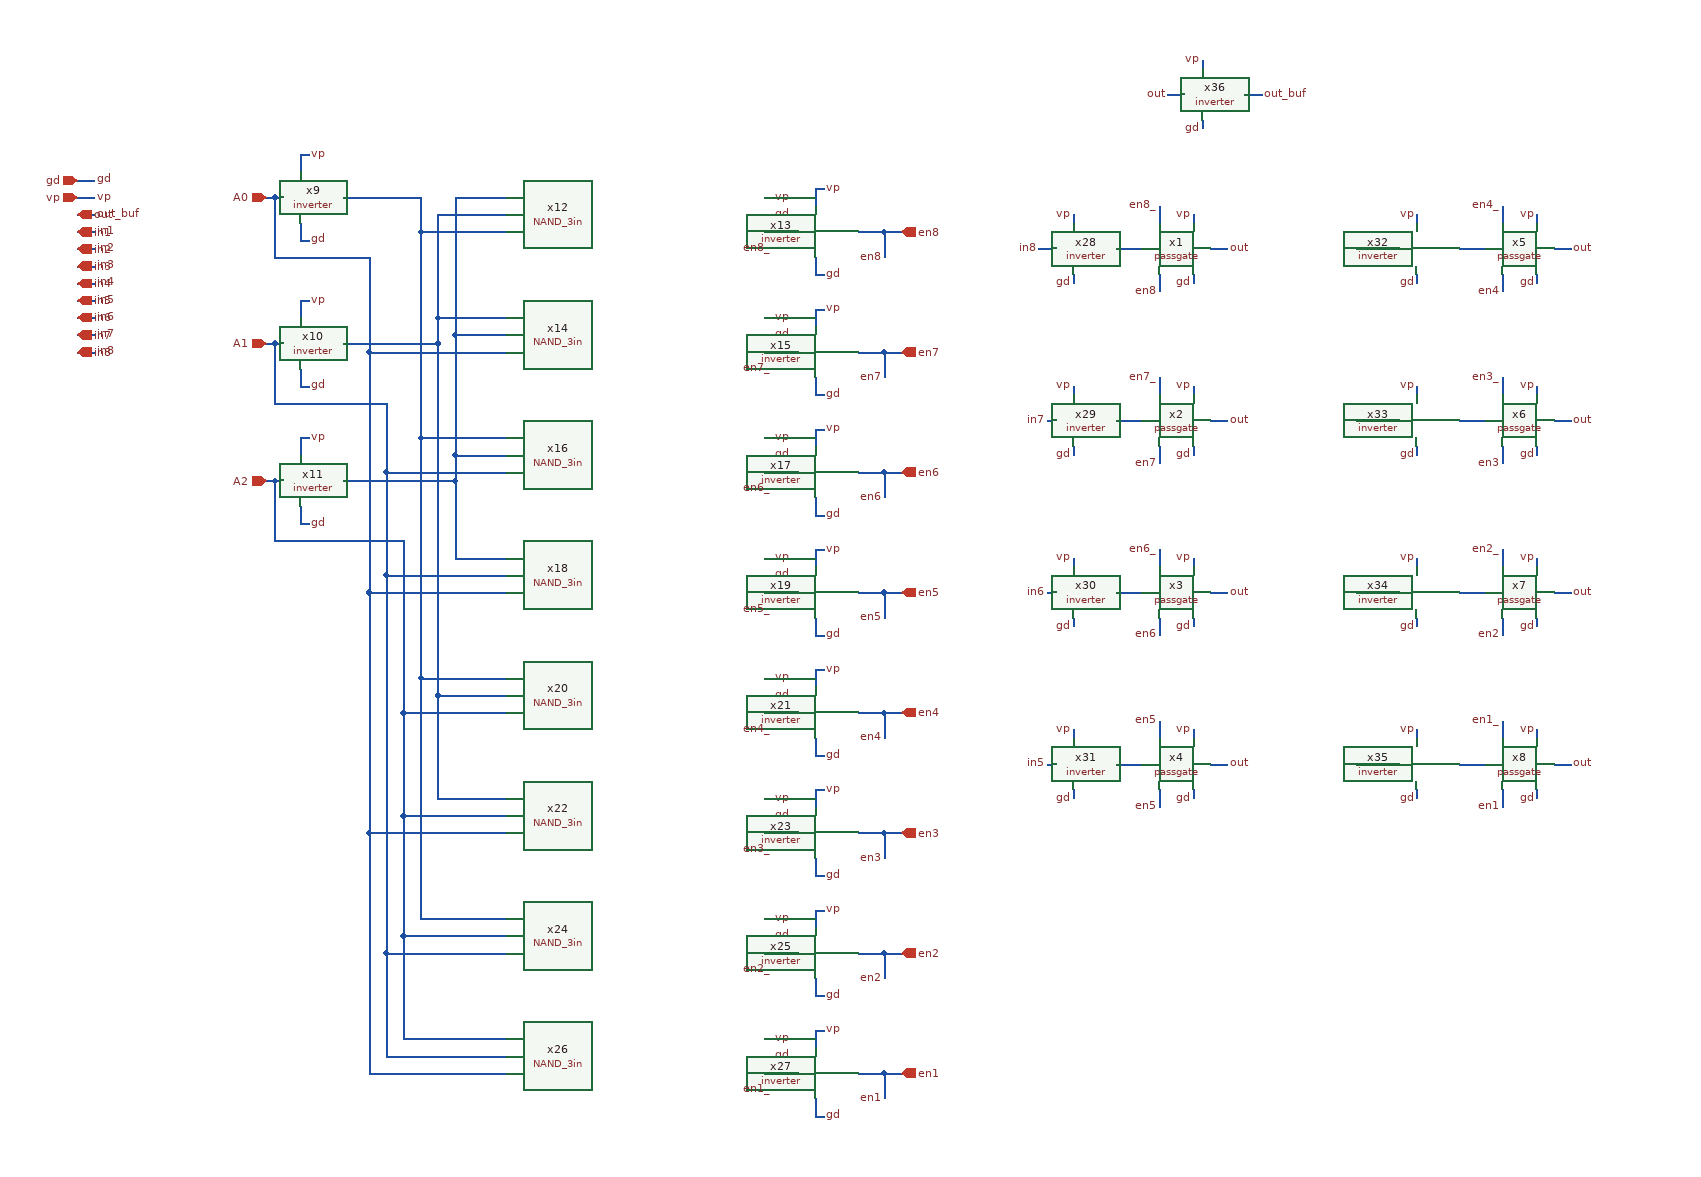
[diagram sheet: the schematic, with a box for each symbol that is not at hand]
v {xschem version=3.4.8RC file_version=1.3}
G {}
K {}
V {}
S {}
F {}
E {}
N 80 -100 100 -100 {lab=gd}
N 80 -80 100 -80 {lab=vp}
N 80 -60 100 -60 {lab=out}
N 80 -40 100 -40 {lab=in1}
N 80 -20 100 -20 {lab=in2}
N 80 0 100 0 {lab=in3}
N 80 20 100 20 {lab=in4}
N 80 60 100 60 {lab=in6}
N 80 80 100 80 {lab=in7}
N 80 100 100 100 {lab=in8}
N 1340 -70 1340 -50 {lab=en8_}
N 1340 10 1340 30 {lab=en8}
N 1380 10 1380 20 {lab=gd}
N 1380 -60 1380 -50 {lab=vp}
N 1400 -20 1420 -20 {lab=out}
N 1340 130 1340 150 {lab=en7_}
N 1340 210 1340 230 {lab=en7}
N 1380 210 1380 220 {lab=gd}
N 1380 140 1380 150 {lab=vp}
N 1210 180 1220 180 {lab=in7}
N 1400 180 1420 180 {lab=out}
N 80 40 100 40 {lab=in5}
N 1340 330 1340 350 {lab=en6_}
N 1340 410 1340 430 {lab=en6}
N 1380 410 1380 420 {lab=gd}
N 1380 340 1380 350 {lab=vp}
N 1210 380 1220 380 {lab=in6}
N 1400 380 1420 380 {lab=out}
N 1340 530 1340 550 {lab=en5}
N 1340 610 1340 630 {lab=en5}
N 1380 610 1380 620 {lab=gd}
N 1380 540 1380 550 {lab=vp}
N 1210 580 1220 580 {lab=in5}
N 1400 580 1420 580 {lab=out}
N 1740 -70 1740 -50 {lab=en4_}
N 1740 10 1740 30 {lab=en4}
N 1780 10 1780 20 {lab=gd}
N 1780 -60 1780 -50 {lab=vp}
N 1570 -20 1580 -20 {lab=#net1}
N 1800 -20 1820 -20 {lab=out}
N 1740 130 1740 150 {lab=en3_}
N 1740 210 1740 230 {lab=en3}
N 1780 210 1780 220 {lab=gd}
N 1780 140 1780 150 {lab=vp}
N 1570 180 1580 180 {lab=#net2}
N 1800 180 1820 180 {lab=out}
N 1740 330 1740 350 {lab=en2_}
N 1740 410 1740 430 {lab=en2}
N 1780 410 1780 420 {lab=gd}
N 1780 340 1780 350 {lab=vp}
N 1570 380 1580 380 {lab=#net3}
N 1800 380 1820 380 {lab=out}
N 1740 530 1740 550 {lab=en1_}
N 1740 610 1740 630 {lab=en1}
N 1780 610 1780 620 {lab=gd}
N 1780 540 1780 550 {lab=vp}
N 1570 580 1580 580 {lab=#net4}
N 1800 580 1820 580 {lab=out}
N 340 -130 350 -130 {lab=vp}
N 340 -130 340 -110 {lab=vp}
N 340 -30 350 -30 {lab=gd}
N 340 -50 340 -30 {lab=gd}
N 310 -80 320 -80 {lab=A0}
N 340 40 350 40 {lab=vp}
N 340 40 340 60 {lab=vp}
N 340 140 350 140 {lab=gd}
N 340 120 340 140 {lab=gd}
N 310 90 320 90 {lab=A1}
N 340 200 350 200 {lab=vp}
N 340 200 340 220 {lab=vp}
N 340 300 350 300 {lab=gd}
N 340 280 340 300 {lab=gd}
N 310 250 320 250 {lab=A2}
N 880 -80 890 -80 {lab=vp}
N 880 -60 890 -60 {lab=gd}
N 940 -90 950 -90 {lab=vp}
N 940 -90 940 -70 {lab=vp}
N 940 10 950 10 {lab=gd}
N 940 -10 940 10 {lab=gd}
N 890 -40 920 -40 {lab=en8_}
N 990 -40 1020 -40 {lab=en8}
N 890 -40 890 -20 {lab=en8_}
N 880 -40 890 -40 {lab=en8_}
N 1020 -40 1020 -10 {lab=en8}
N 880 60 890 60 {lab=vp}
N 880 80 890 80 {lab=gd}
N 940 50 950 50 {lab=vp}
N 940 50 940 70 {lab=vp}
N 940 150 950 150 {lab=gd}
N 940 130 940 150 {lab=gd}
N 890 100 920 100 {lab=en7_}
N 990 100 1020 100 {lab=en7}
N 890 100 890 120 {lab=en7_}
N 880 100 890 100 {lab=en7_}
N 1020 100 1020 130 {lab=en7}
N 880 200 890 200 {lab=vp}
N 880 220 890 220 {lab=gd}
N 940 190 950 190 {lab=vp}
N 940 190 940 210 {lab=vp}
N 940 290 950 290 {lab=gd}
N 940 270 940 290 {lab=gd}
N 890 240 920 240 {lab=en6_}
N 990 240 1020 240 {lab=en6}
N 890 240 890 260 {lab=en6_}
N 880 240 890 240 {lab=en6_}
N 1020 240 1020 270 {lab=en6}
N 880 340 890 340 {lab=vp}
N 880 360 890 360 {lab=gd}
N 940 330 950 330 {lab=vp}
N 940 330 940 350 {lab=vp}
N 940 430 950 430 {lab=gd}
N 940 410 940 430 {lab=gd}
N 890 380 920 380 {lab=en5_}
N 990 380 1020 380 {lab=en5}
N 890 380 890 400 {lab=en5_}
N 880 380 890 380 {lab=en5_}
N 1020 380 1020 410 {lab=en5}
N 880 480 890 480 {lab=vp}
N 880 500 890 500 {lab=gd}
N 940 470 950 470 {lab=vp}
N 940 470 940 490 {lab=vp}
N 940 570 950 570 {lab=gd}
N 940 550 940 570 {lab=gd}
N 890 520 920 520 {lab=en4_}
N 990 520 1020 520 {lab=en4}
N 890 520 890 540 {lab=en4_}
N 880 520 890 520 {lab=en4_}
N 1020 520 1020 550 {lab=en4}
N 880 620 890 620 {lab=vp}
N 880 640 890 640 {lab=gd}
N 940 610 950 610 {lab=vp}
N 940 610 940 630 {lab=vp}
N 940 710 950 710 {lab=gd}
N 940 690 940 710 {lab=gd}
N 890 660 920 660 {lab=en3_}
N 990 660 1020 660 {lab=en3}
N 890 660 890 680 {lab=en3_}
N 880 660 890 660 {lab=en3_}
N 1020 660 1020 690 {lab=en3}
N 880 760 890 760 {lab=vp}
N 880 780 890 780 {lab=gd}
N 940 750 950 750 {lab=vp}
N 940 750 940 770 {lab=vp}
N 940 850 950 850 {lab=gd}
N 940 830 940 850 {lab=gd}
N 890 800 920 800 {lab=en2_}
N 990 800 1020 800 {lab=en2}
N 890 800 890 820 {lab=en2_}
N 880 800 890 800 {lab=en2_}
N 1020 800 1020 830 {lab=en2}
N 880 900 890 900 {lab=vp}
N 880 920 890 920 {lab=gd}
N 940 890 950 890 {lab=vp}
N 940 890 940 910 {lab=vp}
N 940 990 950 990 {lab=gd}
N 940 970 940 990 {lab=gd}
N 890 940 920 940 {lab=en1_}
N 990 940 1020 940 {lab=en1}
N 890 940 890 960 {lab=en1_}
N 880 940 890 940 {lab=en1_}
N 1020 940 1020 970 {lab=en1}
N 420 660 420 940 {lab=A0}
N 310 -80 310 -10 {lab=A0}
N 300 -80 310 -80 {lab=A0}
N 310 -10 420 -10 {lab=A0}
N 310 90 310 160 {lab=A1}
N 300 90 310 90 {lab=A1}
N 310 160 440 160 {lab=A1}
N 310 250 310 320 {lab=A2}
N 300 250 310 250 {lab=A2}
N 310 320 460 320 {lab=A2}
N 390 -80 480 -80 {lab=#net5}
N 390 90 500 90 {lab=#net6}
N 500 60 500 90 {lab=#net6}
N 390 250 520 250 {lab=#net7}
N 520 220 520 250 {lab=#net7}
N 480 -40 580 -40 {lab=#net5}
N 480 -80 480 -40 {lab=#net5}
N 500 -60 580 -60 {lab=#net6}
N 520 -80 580 -80 {lab=#net7}
N 480 200 580 200 {lab=#net5}
N 480 -40 480 200 {lab=#net5}
N 480 480 580 480 {lab=#net5}
N 480 200 480 480 {lab=#net5}
N 480 760 580 760 {lab=#net5}
N 480 480 480 760 {lab=#net5}
N 500 60 580 60 {lab=#net6}
N 500 -60 500 60 {lab=#net6}
N 500 620 580 620 {lab=#net6}
N 500 500 500 620 {lab=#net6}
N 500 500 580 500 {lab=#net6}
N 500 90 500 500 {lab=#net6}
N 520 80 580 80 {lab=#net7}
N 520 -80 520 80 {lab=#net7}
N 520 220 580 220 {lab=#net7}
N 520 80 520 220 {lab=#net7}
N 520 340 580 340 {lab=#net7}
N 520 250 520 340 {lab=#net7}
N 460 900 580 900 {lab=A2}
N 460 780 460 900 {lab=A2}
N 460 780 580 780 {lab=A2}
N 460 640 460 780 {lab=A2}
N 460 640 580 640 {lab=A2}
N 460 520 460 640 {lab=A2}
N 460 520 580 520 {lab=A2}
N 460 320 460 520 {lab=A2}
N 440 920 580 920 {lab=A1}
N 440 800 440 920 {lab=A1}
N 440 800 580 800 {lab=A1}
N 440 360 440 800 {lab=A1}
N 440 240 580 240 {lab=A1}
N 440 160 440 240 {lab=A1}
N 440 360 580 360 {lab=A1}
N 440 240 440 360 {lab=A1}
N 420 100 580 100 {lab=A0}
N 420 -10 420 100 {lab=A0}
N 420 380 580 380 {lab=A0}
N 420 100 420 380 {lab=A0}
N 420 660 580 660 {lab=A0}
N 420 380 420 660 {lab=A0}
N 420 940 580 940 {lab=A0}
N 1020 -40 1040 -40 {lab=en8}
N 1020 100 1040 100 {lab=en7}
N 1020 240 1040 240 {lab=en6}
N 1020 380 1040 380 {lab=en5}
N 1020 520 1040 520 {lab=en4}
N 1020 660 1040 660 {lab=en3}
N 1020 800 1040 800 {lab=en2}
N 1020 940 1040 940 {lab=en1}
N 1290 -20 1320 -20 {lab=#net8}
N 1240 -60 1240 -50 {lab=vp}
N 1240 10 1240 20 {lab=gd}
N 1200 -20 1220 -20 {lab=in8}
N 1290 180 1320 180 {lab=#net9}
N 1240 140 1240 150 {lab=vp}
N 1240 210 1240 220 {lab=gd}
N 1290 380 1320 380 {lab=#net10}
N 1240 340 1240 350 {lab=vp}
N 1240 410 1240 420 {lab=gd}
N 1290 580 1320 580 {lab=#net11}
N 1240 540 1240 550 {lab=vp}
N 1240 610 1240 620 {lab=gd}
N 1610 180 1620 180 {lab=#net12}
N 1610 380 1620 380 {lab=#net13}
N 1610 580 1620 580 {lab=#net14}
N 1690 -20 1720 -20 {lab=#net15}
N 1640 -60 1640 -50 {lab=vp}
N 1640 10 1640 20 {lab=gd}
N 1600 -20 1620 -20 {lab=in4}
N 1690 180 1720 180 {lab=#net16}
N 1640 140 1640 150 {lab=vp}
N 1640 210 1640 220 {lab=gd}
N 1690 380 1720 380 {lab=#net17}
N 1640 340 1640 350 {lab=vp}
N 1640 410 1640 420 {lab=gd}
N 1690 580 1720 580 {lab=#net18}
N 1640 540 1640 550 {lab=vp}
N 1640 610 1640 620 {lab=gd}
N 1390 -240 1390 -230 {lab=vp}
N 1390 -170 1390 -160 {lab=gd}
N 1440 -200 1460 -200 {lab=out_buf}
N 1350 -200 1370 -200 {lab=out}
C {/foss/designs/CHIP-PLL/divider/schematics/passgate.sym} 1340 0 0 0 {name=x1}
C {iopin.sym} 80 -100 2 0 {name=p1 lab=gd}
C {lab_pin.sym} 100 -100 2 0 {name=p4 sig_type=std_logic lab=gd}
C {iopin.sym} 80 -80 2 0 {name=p5 lab=vp}
C {lab_pin.sym} 100 -80 2 0 {name=p6 sig_type=std_logic lab=vp}
C {opin.sym} 80 -60 2 0 {name=p2 lab=out}
C {lab_pin.sym} 100 -60 2 0 {name=p3 sig_type=std_logic lab=out_buf}
C {ipin.sym} 80 -40 2 1 {name=p7 lab=in1}
C {lab_pin.sym} 100 -40 2 0 {name=p8 sig_type=std_logic lab=in1}
C {ipin.sym} 80 -20 2 1 {name=p9 lab=in2}
C {lab_pin.sym} 100 -20 2 0 {name=p10 sig_type=std_logic lab=in2}
C {ipin.sym} 80 0 2 1 {name=p11 lab=in3}
C {lab_pin.sym} 100 0 2 0 {name=p12 sig_type=std_logic lab=in3}
C {ipin.sym} 80 20 2 1 {name=p13 lab=in4}
C {lab_pin.sym} 100 20 2 0 {name=p14 sig_type=std_logic lab=in4}
C {ipin.sym} 80 40 2 1 {name=p15 lab=in5}
C {lab_pin.sym} 100 40 2 0 {name=p16 sig_type=std_logic lab=in5}
C {ipin.sym} 80 60 2 1 {name=p17 lab=in6}
C {lab_pin.sym} 100 60 2 0 {name=p18 sig_type=std_logic lab=in6}
C {ipin.sym} 80 80 2 1 {name=p19 lab=in7}
C {lab_pin.sym} 100 80 2 0 {name=p20 sig_type=std_logic lab=in7}
C {ipin.sym} 80 100 2 1 {name=p21 lab=in8}
C {lab_pin.sym} 100 100 2 0 {name=p22 sig_type=std_logic lab=in8}
C {lab_pin.sym} 1380 20 3 0 {name=p23 sig_type=std_logic lab=gd}
C {lab_pin.sym} 1340 -70 1 0 {name=p25 sig_type=std_logic lab=en8_}
C {lab_pin.sym} 1340 30 3 0 {name=p26 sig_type=std_logic lab=en8}
C {lab_pin.sym} 1200 -20 0 0 {name=p27 sig_type=std_logic lab=in8}
C {lab_pin.sym} 1420 -20 2 0 {name=p28 sig_type=std_logic lab=out}
C {/foss/designs/CHIP-PLL/divider/schematics/passgate.sym} 1340 200 0 0 {name=x2}
C {lab_pin.sym} 1380 220 3 0 {name=p29 sig_type=std_logic lab=gd}
C {lab_pin.sym} 1340 130 1 0 {name=p31 sig_type=std_logic lab=en7_}
C {lab_pin.sym} 1340 230 3 0 {name=p32 sig_type=std_logic lab=en7}
C {lab_pin.sym} 1210 180 0 0 {name=p33 sig_type=std_logic lab=in7}
C {lab_pin.sym} 1420 180 2 0 {name=p34 sig_type=std_logic lab=out}
C {/foss/designs/CHIP-PLL/divider/schematics/passgate.sym} 1340 400 0 0 {name=x3}
C {lab_pin.sym} 1380 420 3 0 {name=p35 sig_type=std_logic lab=gd}
C {lab_pin.sym} 1340 330 1 0 {name=p37 sig_type=std_logic lab=en6_}
C {lab_pin.sym} 1340 430 3 0 {name=p38 sig_type=std_logic lab=en6}
C {lab_pin.sym} 1210 380 0 0 {name=p39 sig_type=std_logic lab=in6
}
C {lab_pin.sym} 1420 380 2 0 {name=p40 sig_type=std_logic lab=out}
C {/foss/designs/CHIP-PLL/divider/schematics/passgate.sym} 1340 600 0 0 {name=x4}
C {lab_pin.sym} 1380 620 3 0 {name=p41 sig_type=std_logic lab=gd}
C {lab_pin.sym} 1340 530 1 0 {name=p43 sig_type=std_logic lab=en5
_}
C {lab_pin.sym} 1340 630 3 0 {name=p44 sig_type=std_logic lab=en5}
C {lab_pin.sym} 1210 580 0 0 {name=p45 sig_type=std_logic lab=in5}
C {lab_pin.sym} 1420 580 2 0 {name=p46 sig_type=std_logic lab=out}
C {/foss/designs/CHIP-PLL/divider/schematics/passgate.sym} 1740 0 0 0 {name=x5}
C {lab_pin.sym} 1780 20 3 0 {name=p47 sig_type=std_logic lab=gd}
C {lab_pin.sym} 1740 -70 1 0 {name=p49 sig_type=std_logic lab=en4_}
C {lab_pin.sym} 1740 30 3 0 {name=p50 sig_type=std_logic lab=en4}
C {lab_pin.sym} 1600 -20 0 0 {name=p51 sig_type=std_logic lab=in4}
C {lab_pin.sym} 1820 -20 2 0 {name=p52 sig_type=std_logic lab=out}
C {/foss/designs/CHIP-PLL/divider/schematics/passgate.sym} 1740 200 0 0 {name=x6}
C {lab_pin.sym} 1780 220 3 0 {name=p53 sig_type=std_logic lab=gd}
C {lab_pin.sym} 1740 130 1 0 {name=p55 sig_type=std_logic lab=en3_}
C {lab_pin.sym} 1740 230 3 0 {name=p56 sig_type=std_logic lab=en3}
C {lab_pin.sym} 1600 180 0 0 {name=p57 sig_type=std_logic lab=in3}
C {lab_pin.sym} 1820 180 2 0 {name=p58 sig_type=std_logic lab=out}
C {/foss/designs/CHIP-PLL/divider/schematics/passgate.sym} 1740 400 0 0 {name=x7}
C {lab_pin.sym} 1780 420 3 0 {name=p59 sig_type=std_logic lab=gd}
C {lab_pin.sym} 1740 330 1 0 {name=p61 sig_type=std_logic lab=en2_}
C {lab_pin.sym} 1740 430 3 0 {name=p62 sig_type=std_logic lab=en2}
C {lab_pin.sym} 1600 380 0 0 {name=p63 sig_type=std_logic lab=in2}
C {lab_pin.sym} 1820 380 2 0 {name=p64 sig_type=std_logic lab=out}
C {/foss/designs/CHIP-PLL/divider/schematics/passgate.sym} 1740 600 0 0 {name=x8}
C {lab_pin.sym} 1780 620 3 0 {name=p65 sig_type=std_logic lab=gd}
C {lab_pin.sym} 1740 530 1 0 {name=p67 sig_type=std_logic lab=en1_
_}
C {lab_pin.sym} 1740 630 3 0 {name=p68 sig_type=std_logic lab=en1}
C {lab_pin.sym} 1600 580 0 0 {name=p69 sig_type=std_logic lab=in1}
C {lab_pin.sym} 1820 580 2 0 {name=p70 sig_type=std_logic lab=out}
C {/foss/designs/CHIP-PLL/divider/schematics/inverter.sym} 340 -80 0 0 {name=x9}
C {lab_pin.sym} 350 -30 2 0 {name=p71 sig_type=std_logic lab=gd}
C {lab_pin.sym} 350 -130 2 0 {name=p72 sig_type=std_logic lab=vp}
C {ipin.sym} 300 -80 0 0 {name=p73 lab=A0}
C {/foss/designs/CHIP-PLL/divider/schematics/inverter.sym} 340 90 0 0 {name=x10}
C {lab_pin.sym} 350 140 2 0 {name=p74 sig_type=std_logic lab=gd}
C {lab_pin.sym} 350 40 2 0 {name=p75 sig_type=std_logic lab=vp}
C {ipin.sym} 300 90 0 0 {name=p76 lab=A1}
C {/foss/designs/CHIP-PLL/divider/schematics/inverter.sym} 340 250 0 0 {name=x11}
C {lab_pin.sym} 350 300 2 0 {name=p77 sig_type=std_logic lab=gd}
C {lab_pin.sym} 350 200 2 0 {name=p78 sig_type=std_logic lab=vp}
C {ipin.sym} 300 250 0 0 {name=p79 lab=A2}
C {lab_pin.sym} 1380 -60 1 0 {name=p24 sig_type=std_logic lab=vp}
C {lab_pin.sym} 1780 -60 1 0 {name=p30 sig_type=std_logic lab=vp}
C {lab_pin.sym} 1380 140 1 0 {name=p36 sig_type=std_logic lab=vp}
C {lab_pin.sym} 1780 140 1 0 {name=p42 sig_type=std_logic lab=vp}
C {lab_pin.sym} 1380 340 1 0 {name=p48 sig_type=std_logic lab=vp}
C {lab_pin.sym} 1780 340 1 0 {name=p54 sig_type=std_logic lab=vp}
C {lab_pin.sym} 1380 540 1 0 {name=p60 sig_type=std_logic lab=vp}
C {lab_pin.sym} 1780 540 1 0 {name=p66 sig_type=std_logic lab=vp}
C {/foss/designs/CHIP-PLL/divider/schematics/NAND_3in.sym} 730 -60 0 0 {name=x12}
C {lab_pin.sym} 890 -80 2 0 {name=p80 sig_type=std_logic lab=vp}
C {lab_pin.sym} 890 -60 2 0 {name=p81 sig_type=std_logic lab=gd}
C {/foss/designs/CHIP-PLL/divider/schematics/inverter.sym} 940 -40 0 0 {name=x13}
C {lab_pin.sym} 950 10 2 0 {name=p82 sig_type=std_logic lab=gd}
C {lab_pin.sym} 950 -90 2 0 {name=p83 sig_type=std_logic lab=vp}
C {lab_pin.sym} 890 -20 3 0 {name=p84 sig_type=std_logic lab=en8_}
C {lab_pin.sym} 1020 -10 3 0 {name=p85 sig_type=std_logic lab=en8}
C {/foss/designs/CHIP-PLL/divider/schematics/NAND_3in.sym} 730 80 0 0 {name=x14}
C {lab_pin.sym} 890 60 2 0 {name=p86 sig_type=std_logic lab=vp}
C {lab_pin.sym} 890 80 2 0 {name=p87 sig_type=std_logic lab=gd}
C {/foss/designs/CHIP-PLL/divider/schematics/inverter.sym} 940 100 0 0 {name=x15}
C {lab_pin.sym} 950 150 2 0 {name=p88 sig_type=std_logic lab=gd}
C {lab_pin.sym} 950 50 2 0 {name=p89 sig_type=std_logic lab=vp}
C {lab_pin.sym} 890 120 3 0 {name=p90 sig_type=std_logic lab=en7_}
C {lab_pin.sym} 1020 130 3 0 {name=p91 sig_type=std_logic lab=en7}
C {/foss/designs/CHIP-PLL/divider/schematics/NAND_3in.sym} 730 220 0 0 {name=x16}
C {lab_pin.sym} 890 200 2 0 {name=p92 sig_type=std_logic lab=vp}
C {lab_pin.sym} 890 220 2 0 {name=p93 sig_type=std_logic lab=gd}
C {/foss/designs/CHIP-PLL/divider/schematics/inverter.sym} 940 240 0 0 {name=x17}
C {lab_pin.sym} 950 290 2 0 {name=p94 sig_type=std_logic lab=gd}
C {lab_pin.sym} 950 190 2 0 {name=p95 sig_type=std_logic lab=vp}
C {lab_pin.sym} 890 260 3 0 {name=p96 sig_type=std_logic lab=en6_}
C {lab_pin.sym} 1020 270 3 0 {name=p97 sig_type=std_logic lab=en6}
C {/foss/designs/CHIP-PLL/divider/schematics/NAND_3in.sym} 730 360 0 0 {name=x18}
C {lab_pin.sym} 890 340 2 0 {name=p98 sig_type=std_logic lab=vp}
C {lab_pin.sym} 890 360 2 0 {name=p99 sig_type=std_logic lab=gd}
C {/foss/designs/CHIP-PLL/divider/schematics/inverter.sym} 940 380 0 0 {name=x19}
C {lab_pin.sym} 950 430 2 0 {name=p100 sig_type=std_logic lab=gd}
C {lab_pin.sym} 950 330 2 0 {name=p101 sig_type=std_logic lab=vp}
C {lab_pin.sym} 890 400 3 0 {name=p102 sig_type=std_logic lab=en5_}
C {lab_pin.sym} 1020 410 3 0 {name=p103 sig_type=std_logic lab=en5}
C {/foss/designs/CHIP-PLL/divider/schematics/NAND_3in.sym} 730 500 0 0 {name=x20}
C {lab_pin.sym} 890 480 2 0 {name=p104 sig_type=std_logic lab=vp}
C {lab_pin.sym} 890 500 2 0 {name=p105 sig_type=std_logic lab=gd}
C {/foss/designs/CHIP-PLL/divider/schematics/inverter.sym} 940 520 0 0 {name=x21}
C {lab_pin.sym} 950 570 2 0 {name=p106 sig_type=std_logic lab=gd}
C {lab_pin.sym} 950 470 2 0 {name=p107 sig_type=std_logic lab=vp}
C {lab_pin.sym} 890 540 3 0 {name=p108 sig_type=std_logic lab=en4_}
C {lab_pin.sym} 1020 550 3 0 {name=p109 sig_type=std_logic lab=en4}
C {/foss/designs/CHIP-PLL/divider/schematics/NAND_3in.sym} 730 640 0 0 {name=x22}
C {lab_pin.sym} 890 620 2 0 {name=p110 sig_type=std_logic lab=vp}
C {lab_pin.sym} 890 640 2 0 {name=p111 sig_type=std_logic lab=gd}
C {/foss/designs/CHIP-PLL/divider/schematics/inverter.sym} 940 660 0 0 {name=x23}
C {lab_pin.sym} 950 710 2 0 {name=p112 sig_type=std_logic lab=gd}
C {lab_pin.sym} 950 610 2 0 {name=p113 sig_type=std_logic lab=vp}
C {lab_pin.sym} 890 680 3 0 {name=p114 sig_type=std_logic lab=en3_}
C {lab_pin.sym} 1020 690 3 0 {name=p115 sig_type=std_logic lab=en3}
C {/foss/designs/CHIP-PLL/divider/schematics/NAND_3in.sym} 730 780 0 0 {name=x24}
C {lab_pin.sym} 890 760 2 0 {name=p116 sig_type=std_logic lab=vp}
C {lab_pin.sym} 890 780 2 0 {name=p117 sig_type=std_logic lab=gd}
C {/foss/designs/CHIP-PLL/divider/schematics/inverter.sym} 940 800 0 0 {name=x25}
C {lab_pin.sym} 950 850 2 0 {name=p118 sig_type=std_logic lab=gd}
C {lab_pin.sym} 950 750 2 0 {name=p119 sig_type=std_logic lab=vp}
C {lab_pin.sym} 890 820 3 0 {name=p120 sig_type=std_logic lab=en2_}
C {lab_pin.sym} 1020 830 3 0 {name=p121 sig_type=std_logic lab=en2}
C {/foss/designs/CHIP-PLL/divider/schematics/NAND_3in.sym} 730 920 0 0 {name=x26}
C {lab_pin.sym} 890 900 2 0 {name=p122 sig_type=std_logic lab=vp}
C {lab_pin.sym} 890 920 2 0 {name=p123 sig_type=std_logic lab=gd}
C {/foss/designs/CHIP-PLL/divider/schematics/inverter.sym} 940 940 0 0 {name=x27}
C {lab_pin.sym} 950 990 2 0 {name=p124 sig_type=std_logic lab=gd}
C {lab_pin.sym} 950 890 2 0 {name=p125 sig_type=std_logic lab=vp}
C {lab_pin.sym} 890 960 3 0 {name=p126 sig_type=std_logic lab=en1_}
C {lab_pin.sym} 1020 970 3 0 {name=p127 sig_type=std_logic lab=en1}
C {opin.sym} 1040 -40 0 0 {name=p128 lab=en8}
C {opin.sym} 1040 100 0 0 {name=p129 lab=en7}
C {opin.sym} 1040 240 0 0 {name=p130 lab=en6}
C {opin.sym} 1040 380 0 0 {name=p131 lab=en5}
C {opin.sym} 1040 520 0 0 {name=p132 lab=en4}
C {opin.sym} 1040 660 0 0 {name=p133 lab=en3}
C {opin.sym} 1040 800 0 0 {name=p134 lab=en2}
C {opin.sym} 1040 940 0 0 {name=p135 lab=en1}
C {/foss/designs/CHIP-PLL/divider/schematics/inverter.sym} 1240 -20 0 0 {name=x28}
C {lab_pin.sym} 1240 -60 1 0 {name=p136 sig_type=std_logic lab=vp}
C {lab_pin.sym} 1240 20 3 0 {name=p137 sig_type=std_logic lab=gd}
C {/foss/designs/CHIP-PLL/divider/schematics/inverter.sym} 1240 180 0 0 {name=x29}
C {lab_pin.sym} 1240 140 1 0 {name=p138 sig_type=std_logic lab=vp}
C {lab_pin.sym} 1240 220 3 0 {name=p139 sig_type=std_logic lab=gd}
C {/foss/designs/CHIP-PLL/divider/schematics/inverter.sym} 1240 380 0 0 {name=x30}
C {lab_pin.sym} 1240 340 1 0 {name=p140 sig_type=std_logic lab=vp}
C {lab_pin.sym} 1240 420 3 0 {name=p141 sig_type=std_logic lab=gd}
C {/foss/designs/CHIP-PLL/divider/schematics/inverter.sym} 1240 580 0 0 {name=x31}
C {lab_pin.sym} 1240 540 1 0 {name=p142 sig_type=std_logic lab=vp}
C {lab_pin.sym} 1240 620 3 0 {name=p143 sig_type=std_logic lab=gd}
C {/foss/designs/CHIP-PLL/divider/schematics/inverter.sym} 1640 -20 0 0 {name=x32}
C {lab_pin.sym} 1640 -60 1 0 {name=p144 sig_type=std_logic lab=vp}
C {lab_pin.sym} 1640 20 3 0 {name=p145 sig_type=std_logic lab=gd}
C {/foss/designs/CHIP-PLL/divider/schematics/inverter.sym} 1640 180 0 0 {name=x33}
C {lab_pin.sym} 1640 140 1 0 {name=p146 sig_type=std_logic lab=vp}
C {lab_pin.sym} 1640 220 3 0 {name=p147 sig_type=std_logic lab=gd}
C {/foss/designs/CHIP-PLL/divider/schematics/inverter.sym} 1640 380 0 0 {name=x34}
C {lab_pin.sym} 1640 340 1 0 {name=p148 sig_type=std_logic lab=vp}
C {lab_pin.sym} 1640 420 3 0 {name=p149 sig_type=std_logic lab=gd}
C {/foss/designs/CHIP-PLL/divider/schematics/inverter.sym} 1640 580 0 0 {name=x35}
C {lab_pin.sym} 1640 540 1 0 {name=p150 sig_type=std_logic lab=vp}
C {lab_pin.sym} 1640 620 3 0 {name=p151 sig_type=std_logic lab=gd}
C {/foss/designs/CHIP-PLL/divider/schematics/inverter.sym} 1390 -200 0 0 {name=x36}
C {lab_pin.sym} 1390 -240 1 0 {name=p152 sig_type=std_logic lab=vp}
C {lab_pin.sym} 1390 -160 3 0 {name=p153 sig_type=std_logic lab=gd}
C {lab_pin.sym} 1460 -200 2 0 {name=p154 sig_type=std_logic lab=out_buf}
C {lab_pin.sym} 1350 -200 0 0 {name=p155 sig_type=std_logic lab=out}
